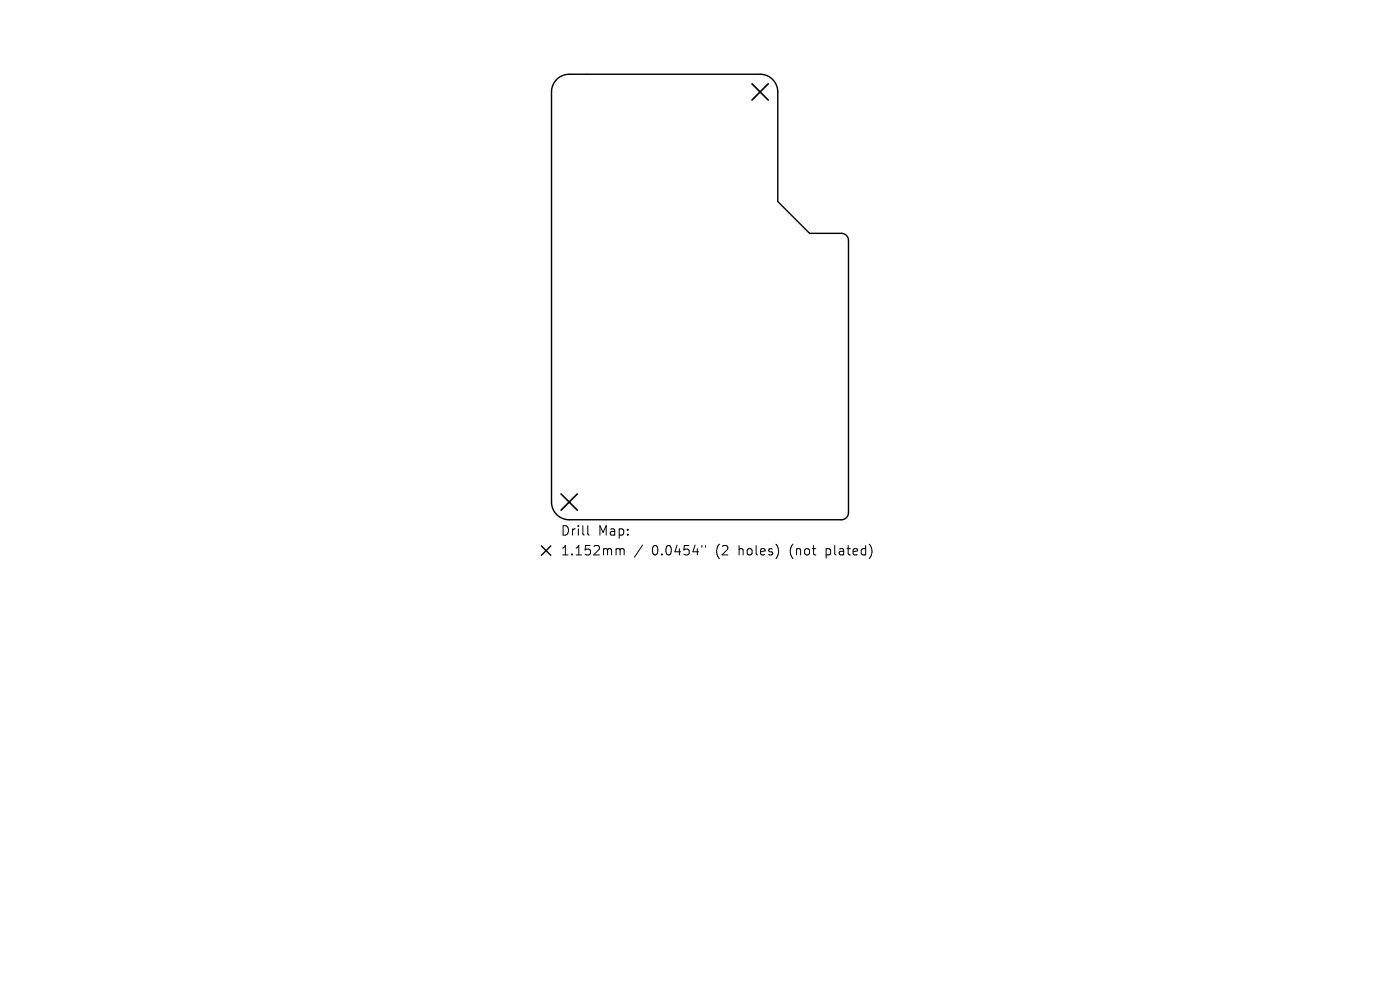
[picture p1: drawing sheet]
<svg xmlns="http://www.w3.org/2000/svg" width="297mm" height="210mm" viewBox="0 0 297 210" stroke-linecap="round" stroke-linejoin="round" font-family="sans-serif">
<defs><g id="words">
<g font-size="2.8">
<text x="118.9" y="113.9">Drill</text>
<text x="126.9" y="113.9">Map:</text>
<text x="118.9" y="118.1">1.152mm</text>
<text x="138.3" y="118.1">0.0454&quot;</text>
<text x="152" y="118.1">(2</text>
<text x="157" y="118.1">holes)</text>
<text x="168" y="118.1">(not</text>
<text x="175.9" y="118.1">plated)</text>
</g>
</g></defs>
<path d="M118.1 16.9a3.8 3.8 0 0 1 2.7-1.1h40.5a3.8 3.8 0 0 1 3.7 3.7v23.3l6.8 6.7h6.7a1.5 1.5 0 0 1 1.5 1.5v57.8a1.5 1.5 0 0 1-1.5 1.5h-57.7a3.8 3.8 0 0 1-3.8-3.8v-87a3.8 3.8 0 0 1 1.1-2.6zM114.9 115.8l2 2M116.9 115.8l-2 2" fill="none" stroke="#000" stroke-width=".3"/>
<path d="M159.5 17.8l3.5 3.4M163 17.8l-3.5 3.4M119 104.8l3.5 3.4M122.5 104.8l-3.5 3.4" fill="none" stroke="#000" stroke-width=".35"/>
<path d="M124.7 111.5v1.7l.3 .3M131 116.4h.3l.3 .3M131.6 116.7l.2-.3 .5 .1 .1 1.2M131.6 116.7v1M136.3 115.6l-1.7 2.6M148.9 115.7v.4M149.6 115.7v.4" fill="none" stroke="#000" stroke-width=".21"/>
<use href="#words"/>
</svg>
